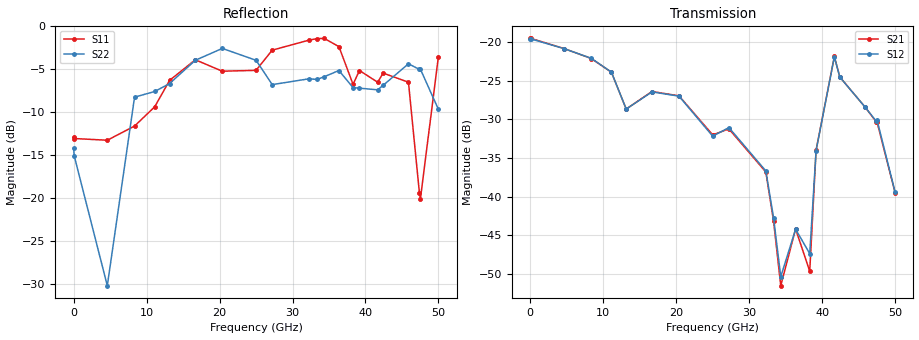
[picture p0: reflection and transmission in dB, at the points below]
!Keysight Technologies,N5245B,MY58422270,A.16.20.02
!Date: Thursday, March 05, 2026 01:22:23
!Correction: S11(C  2-Port  )
!S21(C  2-Port  )
!S12(C  2-Port  )
!S22(C  2-Port  )
!S2P File: Measurements: S11, S21, S12, S22:
# Hz S  dB  R 50
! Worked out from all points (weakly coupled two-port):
!   3201 points, 10 MHz to 50 GHz, reference 50 ohm
!   highest |S21| = -19.56 dB at 72.49 MHz (marker M1); lowest = -51.5 dB at 34.33 GHz (marker M2)
!   lowest |S11| = -20.1 dB at 47.53 GHz (marker M3), VSWR 1.22, Z = 46.1 + j8.78 ohm
!   |S11| at or under -10 dB: start of sweep to 10.13 GHz; 11.36 GHz to 11.92 GHz (564.2 MHz wide, 4.85 % of centre); 46.66 GHz to 48.28 GHz (1.626 GHz wide, 3.42 % of centre)
!   |S22| runs from -30.2 to -2.5 dB; largest |S21 - S12| = 0.0079
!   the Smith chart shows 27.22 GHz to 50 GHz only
!   S11 on the Smith chart (normalised r, x): 27.22 GHz: 0.18, +0.36; 32.28 GHz: 0.42, +1.84; 36.36 GHz: 2.40, -3.37; 42.42 GHz: 1.01, -1.27; 47.39 GHz: 0.84, +0.12; 50 GHz: 0.62, -1.35
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1e7  -12.92 -2.6  -19.57 3.4  -19.64 3.1  -14.19 31.6
7.24875e7  -13.05 -4.5  -19.56 0.6  -19.63 0.4  -15.03 21.3
4.618453e9  -13.25 -116.2  -20.87 -178.9  -20.88 -178.9  -30.17 -117.0
8.352081e9  -11.60 174.9  -22.16 26.5  -22.13 26.5  -8.24 -154.1
1.111715e10  -9.36 108.3  -23.94 -80.6  -23.91 -80.6  -7.58 93.6
1.3148e10  -6.29 64.8  -28.68 -141.5  -28.69 -141.7  -6.66 -16.9
1.667854e10  -3.89 -43.8  -26.42 156.3  -26.47 155.9  -3.95 -139.5
2.038092e10  -5.22 -121.0  -26.98 40.0  -27.02 39.9  -2.57 155.8
2.5005e10  -5.12 179.8  -32.02 -64.6  -32.19 -65.1  -3.95 71.4
2.722331e10  -2.77 139.0  -31.25 -115.3  -31.08 -114.0  -6.78 31.7
3.228479e10  -1.60 55.1  -36.81 50.7  -36.67 49.6  -6.10 -102.7
3.334708e10  -1.43 36.1  -43.18 6.6  -42.74 4.9  -6.18 -126.0
3.433126e10  -1.40 18.5  -51.49 -94.7  -50.34 -91.2  -5.87 -146.6
3.63621e10  -2.36 -22.7  -44.17 108.6  -44.20 114.1  -5.14 174.9
3.829922e10  -6.75 -22.3  -49.63 94.9  -47.35 -68.5  -7.13 139.1
3.917404e10  -5.14 -32.2  -33.96 92.4  -34.05 91.9  -7.19 138.1
4.167354e10  -6.50 -52.6  -21.90 -59.7  -21.96 -59.1  -7.39 118.0
4.242339e10  -5.44 -57.1  -24.54 -119.7  -24.56 -119.8  -6.86 113.7
4.589145e10  -6.50 -117.1  -28.44 55.5  -28.44 54.0  -4.36 62.7
4.739115e10  -19.35 140.8  -30.31 2.1  -30.22 1.5  -5.01 42.4
4.753174e10  -20.06 108.6  -30.39 0.4  -30.12 -0.8  -4.99 40.8
5e10  -3.51 -65.9  -39.49 -136.4  -39.40 -135.3  -9.66 3.3
